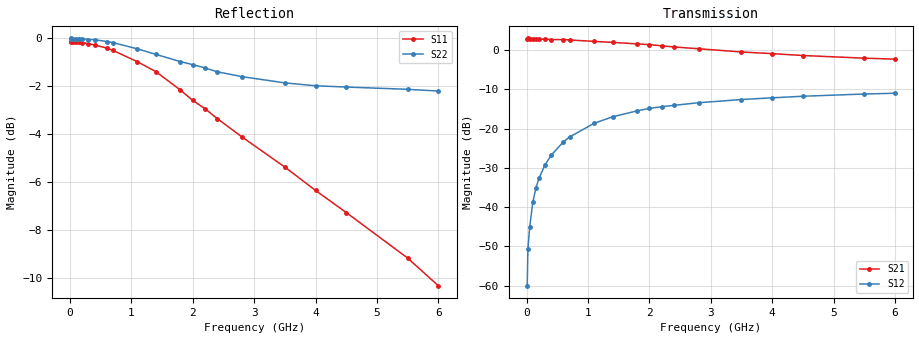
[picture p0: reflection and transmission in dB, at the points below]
! SIEMENS Discrete & RF Semiconductors
! BFY180
! Si NPN RF Bipolar Junction Transistor in MICRO-X
! VCE = 0.75 V  IC = 0.4 mA
! Common Emitter S-Parameters:  May  1997
# GHz  S  MA  R  50
!  f  S11  S21  S12  S22
! GHz  MAG  ANG  MAG  ANG  MAG  ANG  MAG  ANG
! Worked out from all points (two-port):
!   36 points, 10 MHz to 6 GHz, reference 50 ohm
!   highest |S21| = 2.98 dB at 20 MHz (marker M1); lowest = -2.3 dB at 6 GHz (marker M2)
!   |S21| within 3 dB of the highest: start of sweep to 3.049 GHz
!   lowest |S11| = -10.3 dB at 6 GHz (marker M3), VSWR 1.88, Z = 29.2 - j12.9 ohm
!   |S11| at or under -10 dB: 5.857 GHz to end of sweep
!   |S22| runs from -2.2 to 0.0 dB; largest |S21 - S12| = 1.4
!   S11 on the Smith chart (normalised r, x): 10 MHz: open; 700 MHz: 0.68, -4.69; 1.4 GHz: 0.52, -2.30; 2.4 GHz: 0.52, -1.24; 4 GHz: 0.53, -0.65; 6 GHz: 0.58, -0.26
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0.01  0.9841 -0.1  1.369 180.0  0.001 90.3  0.999 -0.2
0.02  0.9878 -0.8  1.41 179.0  0.0029 89.8  0.9999 -0.5
0.05  0.9803 -1.5  1.367 178.1  0.0056 88.9  0.9976 -1.2
0.1  0.9846 -3.3  1.377 175.8  0.0115 88.1  0.9957 -2.4
0.15  0.9831 -5.1  1.372 173.7  0.0174 85.9  0.999 -3.6
0.2  0.9797 -6.7  1.364 171.3  0.0232 84.2  0.9977 -4.8
0.3  0.9745 -10.0  1.382 166.8  0.0346 81.6  0.9944 -7.2
0.4  0.9688 -13.5  1.358 162.5  0.0459 79.4  0.9938 -9.5
0.6  0.9542 -19.9  1.363 153.2  0.068 73.8  0.9846 -14.2
0.7  0.9438 -23.6  1.346 149.7  0.0783 70.8  0.9798 -16.5
1.1  0.8935 -35.7  1.29 133.4  0.1169 60.9  0.9506 -25.4
1.4  0.8521 -45.2  1.254 121.8  0.1414 53.5  0.9258 -31.9
1.8  0.7797 -56.6  1.199 106.8  0.1684 45.7  0.894 -39.3
2  0.7421 -61.9  1.173 99.3  0.1808 41.9  0.8813 -42.9
2.2  0.7129 -66.8  1.134 92.9  0.1902 37.9  0.8674 -46.5
2.4  0.6798 -71.8  1.096 86.4  0.1979 34.7  0.8515 -49.6
2.8  0.6227 -80.0  1.04 74.9  0.2136 29.0  0.8319 -55.6
3.5  0.5385 -93.1  0.946 56.5  0.2346 20.3  0.8072 -65.4
4  0.4813 -102.3  0.901 45.0  0.2468 14.5  0.7961 -72.3
4.5  0.4328 -110.2  0.853 34.5  0.2583 9.2  0.7912 -79.2
5.5  0.3477 -128.3  0.789 15.1  0.2758 -1.0  0.7826 -93.5
6  0.3044 -138.9  0.767 6.5  0.2821 -6.3  0.7761 -100.5
